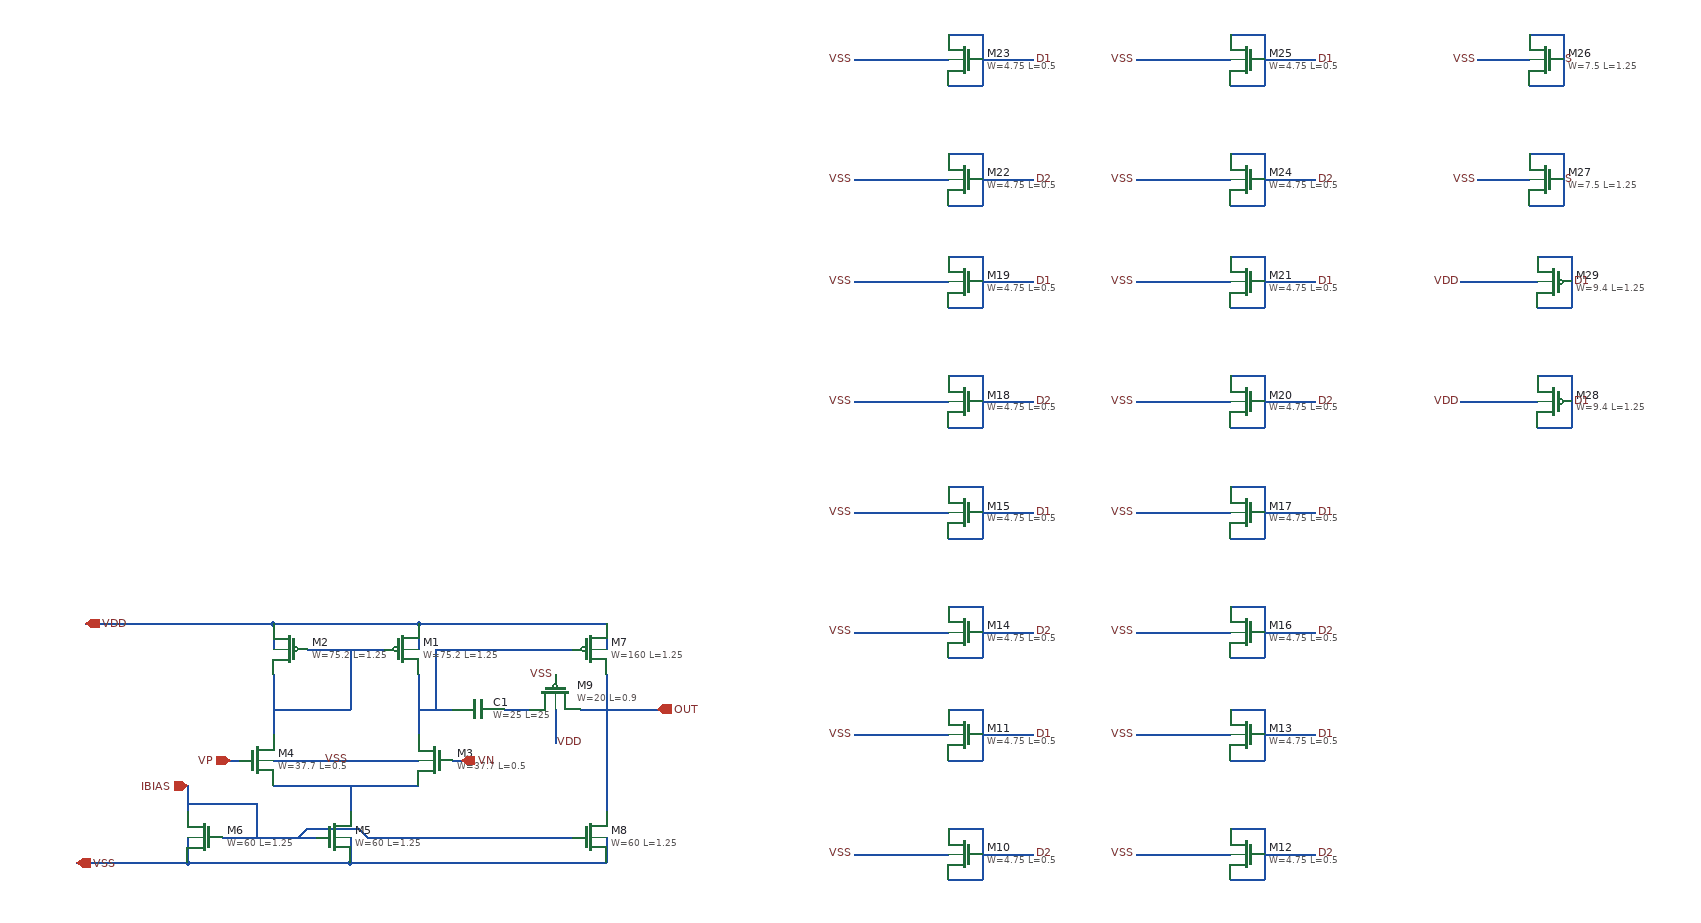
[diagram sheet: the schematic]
v {xschem version=3.4.7 file_version=1.2}
G {}
K {}
V {}
S {}
E {}
N 350 -160 520 -160 {lab=#net1}
N 440 -160 440 -130 {lab=#net1}
N 350 -290 350 -220 {lab=#net2}
N 520 -290 520 -220 {lab=#net3}
N 350 -350 520 -350 {lab=VDD}
N 350 -350 350 -320 {lab=VDD}
N 520 -350 520 -320 {lab=VDD}
N 390 -320 480 -320 {lab=#net2}
N 350 -250 440 -250 {lab=#net2}
N 440 -320 440 -250 {lab=#net2}
N 290 -100 400 -100 {lab=IBIAS}
N 350 -190 520 -190 {lab=VSS}
N 440 -100 440 -70 {lab=VSS}
N 250 -100 250 -70 {lab=VSS}
N 250 -70 440 -70 {lab=VSS}
N 440 -70 740 -70 {lab=VSS}
N 520 -350 740 -350 {lab=VDD}
N 130 -350 350 -350 {lab=VDD}
N 120 -70 250 -70 {lab=VSS}
N 740 -290 740 -130 {lab=OUT}
N 250 -160 250 -130 {lab=IBIAS}
N 460 -100 700 -100 {lab=IBIAS}
N 450 -110 460 -100 {lab=IBIAS}
N 390 -110 450 -110 {lab=IBIAS}
N 380 -100 390 -110 {lab=IBIAS}
N 620 -250 640 -250 {lab=#net4}
N 520 -250 560 -250 {lab=#net3}
N 540 -320 700 -320 {lab=#net3}
N 540 -320 540 -250 {lab=#net3}
N 740 -350 740 -320 {lab=VDD}
N 740 -100 740 -70 {lab=VSS}
N 740 -250 800 -250 {lab=OUT}
N 300 -190 310 -190 {lab=VP}
N 560 -190 570 -190 {lab=VN}
N 710 -250 740 -250 {lab=OUT}
N 250 -140 330 -140 {lab=IBIAS}
N 330 -140 330 -100 {lab=IBIAS}
N 640 -250 650 -250 {lab=#net4}
N 680 -250 680 -210 {lab=VDD}
N 1140 -250 1180 -250 {lab=D1}
N 1180 -250 1180 -190 {lab=D1}
N 1140 -190 1180 -190 {lab=D1}
N 1140 -110 1180 -110 {lab=D2}
N 1180 -110 1180 -50 {lab=D2}
N 1140 -50 1180 -50 {lab=D2}
N 1030 -220 1140 -220 {lab=VSS}
N 1030 -80 1140 -80 {lab=VSS}
N 1180 -220 1240 -220 {lab=D1}
N 1180 -80 1240 -80 {lab=D2}
N 1470 -250 1510 -250 {lab=D1}
N 1510 -250 1510 -190 {lab=D1}
N 1470 -190 1510 -190 {lab=D1}
N 1470 -110 1510 -110 {lab=D2}
N 1510 -110 1510 -50 {lab=D2}
N 1470 -50 1510 -50 {lab=D2}
N 1360 -220 1470 -220 {lab=VSS}
N 1360 -80 1470 -80 {lab=VSS}
N 1510 -220 1570 -220 {lab=D1}
N 1510 -80 1570 -80 {lab=D2}
N 1140 -510 1180 -510 {lab=D1}
N 1180 -510 1180 -450 {lab=D1}
N 1140 -450 1180 -450 {lab=D1}
N 1140 -370 1180 -370 {lab=D2}
N 1180 -370 1180 -310 {lab=D2}
N 1140 -310 1180 -310 {lab=D2}
N 1030 -480 1140 -480 {lab=VSS}
N 1030 -340 1140 -340 {lab=VSS}
N 1180 -480 1240 -480 {lab=D1}
N 1180 -340 1240 -340 {lab=D2}
N 1470 -510 1510 -510 {lab=D1}
N 1510 -510 1510 -450 {lab=D1}
N 1470 -450 1510 -450 {lab=D1}
N 1470 -370 1510 -370 {lab=D2}
N 1510 -370 1510 -310 {lab=D2}
N 1470 -310 1510 -310 {lab=D2}
N 1360 -480 1470 -480 {lab=VSS}
N 1360 -340 1470 -340 {lab=VSS}
N 1510 -480 1570 -480 {lab=D1}
N 1510 -340 1570 -340 {lab=D2}
N 1140 -780 1180 -780 {lab=D1}
N 1180 -780 1180 -720 {lab=D1}
N 1140 -720 1180 -720 {lab=D1}
N 1140 -640 1180 -640 {lab=D2}
N 1180 -640 1180 -580 {lab=D2}
N 1140 -580 1180 -580 {lab=D2}
N 1030 -750 1140 -750 {lab=VSS}
N 1030 -610 1140 -610 {lab=VSS}
N 1180 -750 1240 -750 {lab=D1}
N 1180 -610 1240 -610 {lab=D2}
N 1470 -780 1510 -780 {lab=D1}
N 1510 -780 1510 -720 {lab=D1}
N 1470 -720 1510 -720 {lab=D1}
N 1470 -640 1510 -640 {lab=D2}
N 1510 -640 1510 -580 {lab=D2}
N 1470 -580 1510 -580 {lab=D2}
N 1360 -750 1470 -750 {lab=VSS}
N 1360 -610 1470 -610 {lab=VSS}
N 1510 -750 1570 -750 {lab=D1}
N 1510 -610 1570 -610 {lab=D2}
N 1140 -1040 1180 -1040 {lab=D1}
N 1180 -1040 1180 -980 {lab=D1}
N 1140 -980 1180 -980 {lab=D1}
N 1140 -900 1180 -900 {lab=D2}
N 1180 -900 1180 -840 {lab=D2}
N 1140 -840 1180 -840 {lab=D2}
N 1030 -1010 1140 -1010 {lab=VSS}
N 1030 -870 1140 -870 {lab=VSS}
N 1180 -1010 1240 -1010 {lab=D1}
N 1180 -870 1240 -870 {lab=D2}
N 1470 -1040 1510 -1040 {lab=D1}
N 1510 -1040 1510 -980 {lab=D1}
N 1470 -980 1510 -980 {lab=D1}
N 1470 -900 1510 -900 {lab=D2}
N 1510 -900 1510 -840 {lab=D2}
N 1470 -840 1510 -840 {lab=D2}
N 1360 -1010 1470 -1010 {lab=VSS}
N 1360 -870 1470 -870 {lab=VSS}
N 1510 -1010 1570 -1010 {lab=D1}
N 1510 -870 1570 -870 {lab=D2}
N 1820 -1040 1860 -1040 {lab=VSS}
N 1860 -1040 1860 -980 {lab=VSS}
N 1820 -980 1860 -980 {lab=VSS}
N 1760 -1010 1820 -1010 {lab=VSS}
N 1820 -900 1860 -900 {lab=VSS}
N 1860 -900 1860 -840 {lab=VSS}
N 1820 -840 1860 -840 {lab=VSS}
N 1760 -870 1820 -870 {lab=VSS}
N 1740 -750 1830 -750 {lab=VDD}
N 1830 -780 1870 -780 {lab=D1}
N 1870 -780 1870 -720 {lab=D1}
N 1830 -720 1870 -720 {lab=D1}
N 1830 -640 1870 -640 {lab=D2}
N 1870 -640 1870 -580 {lab=D2}
N 1830 -580 1870 -580 {lab=D2}
N 1740 -610 1830 -610 {lab=VDD}
C {sky130_fd_pr/pfet_g5v0d10v5.sym} 500 -320 0 0 {name=M1
W=75.2
L=1.25
nf=8
mult=1
ad="'int((nf+1)/2) * W/nf * 0.29'" 
pd="'2*int((nf+1)/2) * (W/nf + 0.29)'"
as="'int((nf+2)/2) * W/nf * 0.29'" 
ps="'2*int((nf+2)/2) * (W/nf + 0.29)'"
nrd="'0.29 / W'" nrs="'0.29 / W'"
sa=0 sb=0 sd=0
model=pfet_g5v0d10v5
spiceprefix=X
}
C {sky130_fd_pr/pfet_g5v0d10v5.sym} 370 -320 0 1 {name=M2
W=75.2
L=1.25
nf=8
mult=1
ad="'int((nf+1)/2) * W/nf * 0.29'" 
pd="'2*int((nf+1)/2) * (W/nf + 0.29)'"
as="'int((nf+2)/2) * W/nf * 0.29'" 
ps="'2*int((nf+2)/2) * (W/nf + 0.29)'"
nrd="'0.29 / W'" nrs="'0.29 / W'"
sa=0 sb=0 sd=0
model=pfet_g5v0d10v5
spiceprefix=X
}
C {sky130_fd_pr/nfet_g5v0d10v5.sym} 540 -190 0 1 {name=M3
W=37.7
L=0.5
nf=8
mult=1
ad="'int((nf+1)/2) * W/nf * 0.29'" 
pd="'2*int((nf+1)/2) * (W/nf + 0.29)'"
as="'int((nf+2)/2) * W/nf * 0.29'" 
ps="'2*int((nf+2)/2) * (W/nf + 0.29)'"
nrd="'0.29 / W'" nrs="'0.29 / W'"
sa=0 sb=0 sd=0
model=nfet_g5v0d10v5
spiceprefix=X
}
C {sky130_fd_pr/nfet_g5v0d10v5.sym} 330 -190 0 0 {name=M4
W=37.7
L=0.5
nf=8
mult=1
ad="'int((nf+1)/2) * W/nf * 0.29'" 
pd="'2*int((nf+1)/2) * (W/nf + 0.29)'"
as="'int((nf+2)/2) * W/nf * 0.29'" 
ps="'2*int((nf+2)/2) * (W/nf + 0.29)'"
nrd="'0.29 / W'" nrs="'0.29 / W'"
sa=0 sb=0 sd=0
model=nfet_g5v0d10v5
spiceprefix=X
}
C {sky130_fd_pr/nfet_g5v0d10v5.sym} 420 -100 0 0 {name=M5
W=60
L=1.25
nf=8
mult=1
ad="'int((nf+1)/2) * W/nf * 0.29'" 
pd="'2*int((nf+1)/2) * (W/nf + 0.29)'"
as="'int((nf+2)/2) * W/nf * 0.29'" 
ps="'2*int((nf+2)/2) * (W/nf + 0.29)'"
nrd="'0.29 / W'" nrs="'0.29 / W'"
sa=0 sb=0 sd=0
model=nfet_g5v0d10v5
spiceprefix=X
}
C {sky130_fd_pr/nfet_g5v0d10v5.sym} 270 -100 0 1 {name=M6
W=60
L=1.25
nf=8
mult=1
ad="'int((nf+1)/2) * W/nf * 0.29'" 
pd="'2*int((nf+1)/2) * (W/nf + 0.29)'"
as="'int((nf+2)/2) * W/nf * 0.29'" 
ps="'2*int((nf+2)/2) * (W/nf + 0.29)'"
nrd="'0.29 / W'" nrs="'0.29 / W'"
sa=0 sb=0 sd=0
model=nfet_g5v0d10v5
spiceprefix=X
}
C {sky130_fd_pr/pfet_g5v0d10v5.sym} 720 -320 0 0 {name=M7
W=160
L=1.25
nf=16
mult=1
ad="'int((nf+1)/2) * W/nf * 0.29'" 
pd="'2*int((nf+1)/2) * (W/nf + 0.29)'"
as="'int((nf+2)/2) * W/nf * 0.29'" 
ps="'2*int((nf+2)/2) * (W/nf + 0.29)'"
nrd="'0.29 / W'" nrs="'0.29 / W'"
sa=0 sb=0 sd=0
model=pfet_g5v0d10v5
spiceprefix=X
}
C {sky130_fd_pr/nfet_g5v0d10v5.sym} 720 -100 0 0 {name=M8
W=60
L=1.25
nf=8
mult=1
ad="'int((nf+1)/2) * W/nf * 0.29'" 
pd="'2*int((nf+1)/2) * (W/nf + 0.29)'"
as="'int((nf+2)/2) * W/nf * 0.29'" 
ps="'2*int((nf+2)/2) * (W/nf + 0.29)'"
nrd="'0.29 / W'" nrs="'0.29 / W'"
sa=0 sb=0 sd=0
model=nfet_g5v0d10v5
spiceprefix=X
}
C {iopin.sym} 130 -350 0 1 {name=p1 lab=VDD}
C {iopin.sym} 120 -70 0 1 {name=p2 lab=VSS}
C {sky130_fd_pr/cap_mim_m3_1.sym} 590 -250 1 0 {name=C1 model=cap_mim_m3_1 W=25 L=25 MF=8 spiceprefix=X}
C {ipin.sym} 250 -160 0 0 {name=p3 lab=IBIAS}
C {lab_wire.sym} 440 -190 0 0 {name=p4 sig_type=std_logic lab=VSS}
C {ipin.sym} 300 -190 0 0 {name=p6 lab=VP}
C {ipin.sym} 570 -190 0 1 {name=p7 lab=VN}
C {opin.sym} 800 -250 0 0 {name=p8 lab=OUT}
C {sky130_fd_pr/pfet_g5v0d10v5.sym} 680 -270 3 1 {name=M9
W=20
L=0.9
nf=1
mult=4
ad="'int((nf+1)/2) * W/nf * 0.29'" 
pd="'2*int((nf+1)/2) * (W/nf + 0.29)'"
as="'int((nf+2)/2) * W/nf * 0.29'" 
ps="'2*int((nf+2)/2) * (W/nf + 0.29)'"
nrd="'0.29 / W'" nrs="'0.29 / W'"
sa=0 sb=0 sd=0
model=pfet_g5v0d10v5
spiceprefix=X
}
C {lab_wire.sym} 680 -290 0 0 {name=p5 sig_type=std_logic lab=VSS}
C {lab_wire.sym} 680 -210 2 0 {name=p9 sig_type=std_logic lab=VDD}
C {sky130_fd_pr/nfet_g5v0d10v5.sym} 1160 -80 0 1 {name=M10
W=4.75
L=0.5
nf=1
mult=1
ad="'int((nf+1)/2) * W/nf * 0.29'" 
pd="'2*int((nf+1)/2) * (W/nf + 0.29)'"
as="'int((nf+2)/2) * W/nf * 0.29'" 
ps="'2*int((nf+2)/2) * (W/nf + 0.29)'"
nrd="'0.29 / W'" nrs="'0.29 / W'"
sa=0 sb=0 sd=0
model=nfet_g5v0d10v5
spiceprefix=X
}
C {sky130_fd_pr/nfet_g5v0d10v5.sym} 1160 -220 0 1 {name=M11
W=4.75
L=0.5
nf=1
mult=1
ad="'int((nf+1)/2) * W/nf * 0.29'" 
pd="'2*int((nf+1)/2) * (W/nf + 0.29)'"
as="'int((nf+2)/2) * W/nf * 0.29'" 
ps="'2*int((nf+2)/2) * (W/nf + 0.29)'"
nrd="'0.29 / W'" nrs="'0.29 / W'"
sa=0 sb=0 sd=0
model=nfet_g5v0d10v5
spiceprefix=X
}
C {lab_wire.sym} 1030 -220 0 0 {name=p10 sig_type=std_logic lab=VSS}
C {lab_wire.sym} 1030 -80 0 0 {name=p11 sig_type=std_logic lab=VSS}
C {lab_wire.sym} 1240 -220 0 1 {name=p12 sig_type=std_logic lab=D1}
C {lab_wire.sym} 1240 -80 0 1 {name=p13 sig_type=std_logic lab=D2}
C {sky130_fd_pr/nfet_g5v0d10v5.sym} 1490 -80 0 1 {name=M12
W=4.75
L=0.5
nf=1
mult=1
ad="'int((nf+1)/2) * W/nf * 0.29'" 
pd="'2*int((nf+1)/2) * (W/nf + 0.29)'"
as="'int((nf+2)/2) * W/nf * 0.29'" 
ps="'2*int((nf+2)/2) * (W/nf + 0.29)'"
nrd="'0.29 / W'" nrs="'0.29 / W'"
sa=0 sb=0 sd=0
model=nfet_g5v0d10v5
spiceprefix=X
}
C {sky130_fd_pr/nfet_g5v0d10v5.sym} 1490 -220 0 1 {name=M13
W=4.75
L=0.5
nf=1
mult=1
ad="'int((nf+1)/2) * W/nf * 0.29'" 
pd="'2*int((nf+1)/2) * (W/nf + 0.29)'"
as="'int((nf+2)/2) * W/nf * 0.29'" 
ps="'2*int((nf+2)/2) * (W/nf + 0.29)'"
nrd="'0.29 / W'" nrs="'0.29 / W'"
sa=0 sb=0 sd=0
model=nfet_g5v0d10v5
spiceprefix=X
}
C {lab_wire.sym} 1360 -220 0 0 {name=p14 sig_type=std_logic lab=VSS}
C {lab_wire.sym} 1360 -80 0 0 {name=p15 sig_type=std_logic lab=VSS}
C {lab_wire.sym} 1570 -220 0 1 {name=p16 sig_type=std_logic lab=D1}
C {lab_wire.sym} 1570 -80 0 1 {name=p17 sig_type=std_logic lab=D2}
C {sky130_fd_pr/nfet_g5v0d10v5.sym} 1160 -340 0 1 {name=M14
W=4.75
L=0.5
nf=1
mult=1
ad="'int((nf+1)/2) * W/nf * 0.29'" 
pd="'2*int((nf+1)/2) * (W/nf + 0.29)'"
as="'int((nf+2)/2) * W/nf * 0.29'" 
ps="'2*int((nf+2)/2) * (W/nf + 0.29)'"
nrd="'0.29 / W'" nrs="'0.29 / W'"
sa=0 sb=0 sd=0
model=nfet_g5v0d10v5
spiceprefix=X
}
C {sky130_fd_pr/nfet_g5v0d10v5.sym} 1160 -480 0 1 {name=M15
W=4.75
L=0.5
nf=1
mult=1
ad="'int((nf+1)/2) * W/nf * 0.29'" 
pd="'2*int((nf+1)/2) * (W/nf + 0.29)'"
as="'int((nf+2)/2) * W/nf * 0.29'" 
ps="'2*int((nf+2)/2) * (W/nf + 0.29)'"
nrd="'0.29 / W'" nrs="'0.29 / W'"
sa=0 sb=0 sd=0
model=nfet_g5v0d10v5
spiceprefix=X
}
C {lab_wire.sym} 1030 -480 0 0 {name=p18 sig_type=std_logic lab=VSS}
C {lab_wire.sym} 1030 -340 0 0 {name=p19 sig_type=std_logic lab=VSS}
C {lab_wire.sym} 1240 -480 0 1 {name=p20 sig_type=std_logic lab=D1}
C {lab_wire.sym} 1240 -340 0 1 {name=p21 sig_type=std_logic lab=D2}
C {sky130_fd_pr/nfet_g5v0d10v5.sym} 1490 -340 0 1 {name=M16
W=4.75
L=0.5
nf=1
mult=1
ad="'int((nf+1)/2) * W/nf * 0.29'" 
pd="'2*int((nf+1)/2) * (W/nf + 0.29)'"
as="'int((nf+2)/2) * W/nf * 0.29'" 
ps="'2*int((nf+2)/2) * (W/nf + 0.29)'"
nrd="'0.29 / W'" nrs="'0.29 / W'"
sa=0 sb=0 sd=0
model=nfet_g5v0d10v5
spiceprefix=X
}
C {sky130_fd_pr/nfet_g5v0d10v5.sym} 1490 -480 0 1 {name=M17
W=4.75
L=0.5
nf=1
mult=1
ad="'int((nf+1)/2) * W/nf * 0.29'" 
pd="'2*int((nf+1)/2) * (W/nf + 0.29)'"
as="'int((nf+2)/2) * W/nf * 0.29'" 
ps="'2*int((nf+2)/2) * (W/nf + 0.29)'"
nrd="'0.29 / W'" nrs="'0.29 / W'"
sa=0 sb=0 sd=0
model=nfet_g5v0d10v5
spiceprefix=X
}
C {lab_wire.sym} 1360 -480 0 0 {name=p22 sig_type=std_logic lab=VSS}
C {lab_wire.sym} 1360 -340 0 0 {name=p23 sig_type=std_logic lab=VSS}
C {lab_wire.sym} 1570 -480 0 1 {name=p24 sig_type=std_logic lab=D1}
C {lab_wire.sym} 1570 -340 0 1 {name=p25 sig_type=std_logic lab=D2}
C {sky130_fd_pr/nfet_g5v0d10v5.sym} 1160 -610 0 1 {name=M18
W=4.75
L=0.5
nf=1
mult=1
ad="'int((nf+1)/2) * W/nf * 0.29'" 
pd="'2*int((nf+1)/2) * (W/nf + 0.29)'"
as="'int((nf+2)/2) * W/nf * 0.29'" 
ps="'2*int((nf+2)/2) * (W/nf + 0.29)'"
nrd="'0.29 / W'" nrs="'0.29 / W'"
sa=0 sb=0 sd=0
model=nfet_g5v0d10v5
spiceprefix=X
}
C {sky130_fd_pr/nfet_g5v0d10v5.sym} 1160 -750 0 1 {name=M19
W=4.75
L=0.5
nf=1
mult=1
ad="'int((nf+1)/2) * W/nf * 0.29'" 
pd="'2*int((nf+1)/2) * (W/nf + 0.29)'"
as="'int((nf+2)/2) * W/nf * 0.29'" 
ps="'2*int((nf+2)/2) * (W/nf + 0.29)'"
nrd="'0.29 / W'" nrs="'0.29 / W'"
sa=0 sb=0 sd=0
model=nfet_g5v0d10v5
spiceprefix=X
}
C {lab_wire.sym} 1030 -750 0 0 {name=p26 sig_type=std_logic lab=VSS}
C {lab_wire.sym} 1030 -610 0 0 {name=p27 sig_type=std_logic lab=VSS}
C {lab_wire.sym} 1240 -750 0 1 {name=p28 sig_type=std_logic lab=D1}
C {lab_wire.sym} 1240 -610 0 1 {name=p29 sig_type=std_logic lab=D2}
C {sky130_fd_pr/nfet_g5v0d10v5.sym} 1490 -610 0 1 {name=M20
W=4.75
L=0.5
nf=1
mult=1
ad="'int((nf+1)/2) * W/nf * 0.29'" 
pd="'2*int((nf+1)/2) * (W/nf + 0.29)'"
as="'int((nf+2)/2) * W/nf * 0.29'" 
ps="'2*int((nf+2)/2) * (W/nf + 0.29)'"
nrd="'0.29 / W'" nrs="'0.29 / W'"
sa=0 sb=0 sd=0
model=nfet_g5v0d10v5
spiceprefix=X
}
C {sky130_fd_pr/nfet_g5v0d10v5.sym} 1490 -750 0 1 {name=M21
W=4.75
L=0.5
nf=1
mult=1
ad="'int((nf+1)/2) * W/nf * 0.29'" 
pd="'2*int((nf+1)/2) * (W/nf + 0.29)'"
as="'int((nf+2)/2) * W/nf * 0.29'" 
ps="'2*int((nf+2)/2) * (W/nf + 0.29)'"
nrd="'0.29 / W'" nrs="'0.29 / W'"
sa=0 sb=0 sd=0
model=nfet_g5v0d10v5
spiceprefix=X
}
C {lab_wire.sym} 1360 -750 0 0 {name=p30 sig_type=std_logic lab=VSS}
C {lab_wire.sym} 1360 -610 0 0 {name=p31 sig_type=std_logic lab=VSS}
C {lab_wire.sym} 1570 -750 0 1 {name=p32 sig_type=std_logic lab=D1}
C {lab_wire.sym} 1570 -610 0 1 {name=p33 sig_type=std_logic lab=D2}
C {sky130_fd_pr/nfet_g5v0d10v5.sym} 1160 -870 0 1 {name=M22
W=4.75
L=0.5
nf=1
mult=1
ad="'int((nf+1)/2) * W/nf * 0.29'" 
pd="'2*int((nf+1)/2) * (W/nf + 0.29)'"
as="'int((nf+2)/2) * W/nf * 0.29'" 
ps="'2*int((nf+2)/2) * (W/nf + 0.29)'"
nrd="'0.29 / W'" nrs="'0.29 / W'"
sa=0 sb=0 sd=0
model=nfet_g5v0d10v5
spiceprefix=X
}
C {sky130_fd_pr/nfet_g5v0d10v5.sym} 1160 -1010 0 1 {name=M23
W=4.75
L=0.5
nf=1
mult=1
ad="'int((nf+1)/2) * W/nf * 0.29'" 
pd="'2*int((nf+1)/2) * (W/nf + 0.29)'"
as="'int((nf+2)/2) * W/nf * 0.29'" 
ps="'2*int((nf+2)/2) * (W/nf + 0.29)'"
nrd="'0.29 / W'" nrs="'0.29 / W'"
sa=0 sb=0 sd=0
model=nfet_g5v0d10v5
spiceprefix=X
}
C {lab_wire.sym} 1030 -1010 0 0 {name=p34 sig_type=std_logic lab=VSS}
C {lab_wire.sym} 1030 -870 0 0 {name=p35 sig_type=std_logic lab=VSS}
C {lab_wire.sym} 1240 -1010 0 1 {name=p36 sig_type=std_logic lab=D1}
C {lab_wire.sym} 1240 -870 0 1 {name=p37 sig_type=std_logic lab=D2}
C {sky130_fd_pr/nfet_g5v0d10v5.sym} 1490 -870 0 1 {name=M24
W=4.75
L=0.5
nf=1
mult=1
ad="'int((nf+1)/2) * W/nf * 0.29'" 
pd="'2*int((nf+1)/2) * (W/nf + 0.29)'"
as="'int((nf+2)/2) * W/nf * 0.29'" 
ps="'2*int((nf+2)/2) * (W/nf + 0.29)'"
nrd="'0.29 / W'" nrs="'0.29 / W'"
sa=0 sb=0 sd=0
model=nfet_g5v0d10v5
spiceprefix=X
}
C {sky130_fd_pr/nfet_g5v0d10v5.sym} 1490 -1010 0 1 {name=M25
W=4.75
L=0.5
nf=1
mult=1
ad="'int((nf+1)/2) * W/nf * 0.29'" 
pd="'2*int((nf+1)/2) * (W/nf + 0.29)'"
as="'int((nf+2)/2) * W/nf * 0.29'" 
ps="'2*int((nf+2)/2) * (W/nf + 0.29)'"
nrd="'0.29 / W'" nrs="'0.29 / W'"
sa=0 sb=0 sd=0
model=nfet_g5v0d10v5
spiceprefix=X
}
C {lab_wire.sym} 1360 -1010 0 0 {name=p38 sig_type=std_logic lab=VSS}
C {lab_wire.sym} 1360 -870 0 0 {name=p39 sig_type=std_logic lab=VSS}
C {lab_wire.sym} 1570 -1010 0 1 {name=p40 sig_type=std_logic lab=D1}
C {lab_wire.sym} 1570 -870 0 1 {name=p41 sig_type=std_logic lab=D2}
C {sky130_fd_pr/nfet_g5v0d10v5.sym} 1840 -1010 0 1 {name=M26
W=7.5
L=1.25
nf=1
mult=1
ad="'int((nf+1)/2) * W/nf * 0.29'" 
pd="'2*int((nf+1)/2) * (W/nf + 0.29)'"
as="'int((nf+2)/2) * W/nf * 0.29'" 
ps="'2*int((nf+2)/2) * (W/nf + 0.29)'"
nrd="'0.29 / W'" nrs="'0.29 / W'"
sa=0 sb=0 sd=0
model=nfet_g5v0d10v5
spiceprefix=X
}
C {lab_pin.sym} 1760 -1010 0 0 {name=p42 sig_type=std_logic lab=VSS}
C {lab_pin.sym} 1860 -1010 0 1 {name=p43 sig_type=std_logic lab=S
W=7.5
nf=1}
C {sky130_fd_pr/nfet_g5v0d10v5.sym} 1840 -870 0 1 {name=M27
W=7.5
L=1.25
nf=1
mult=1
ad="'int((nf+1)/2) * W/nf * 0.29'" 
pd="'2*int((nf+1)/2) * (W/nf + 0.29)'"
as="'int((nf+2)/2) * W/nf * 0.29'" 
ps="'2*int((nf+2)/2) * (W/nf + 0.29)'"
nrd="'0.29 / W'" nrs="'0.29 / W'"
sa=0 sb=0 sd=0
model=nfet_g5v0d10v5
spiceprefix=X
}
C {lab_pin.sym} 1760 -870 0 0 {name=p44 sig_type=std_logic lab=VSS}
C {lab_pin.sym} 1860 -870 0 1 {name=p45 sig_type=std_logic lab=S
W=7.5
nf=1}
C {sky130_fd_pr/pfet_g5v0d10v5.sym} 1850 -610 0 1 {name=M28
W=9.4
L=1.25
nf=1
mult=1
ad="'int((nf+1)/2) * W/nf * 0.29'" 
pd="'2*int((nf+1)/2) * (W/nf + 0.29)'"
as="'int((nf+2)/2) * W/nf * 0.29'" 
ps="'2*int((nf+2)/2) * (W/nf + 0.29)'"
nrd="'0.29 / W'" nrs="'0.29 / W'"
sa=0 sb=0 sd=0
model=pfet_g5v0d10v5
spiceprefix=X
}
C {sky130_fd_pr/pfet_g5v0d10v5.sym} 1850 -750 0 1 {name=M29
W=9.4
L=1.25
nf=1
mult=1
ad="'int((nf+1)/2) * W/nf * 0.29'" 
pd="'2*int((nf+1)/2) * (W/nf + 0.29)'"
as="'int((nf+2)/2) * W/nf * 0.29'" 
ps="'2*int((nf+2)/2) * (W/nf + 0.29)'"
nrd="'0.29 / W'" nrs="'0.29 / W'"
sa=0 sb=0 sd=0
model=pfet_g5v0d10v5
spiceprefix=X
}
C {lab_pin.sym} 1740 -750 0 0 {name=p46 sig_type=std_logic lab=VDD}
C {lab_pin.sym} 1740 -610 0 0 {name=p47 sig_type=std_logic lab=VDD}
C {lab_pin.sym} 1870 -610 0 1 {name=p48 sig_type=std_logic lab=D1}
C {lab_pin.sym} 1870 -750 0 1 {name=p49 sig_type=std_logic lab=D1}
